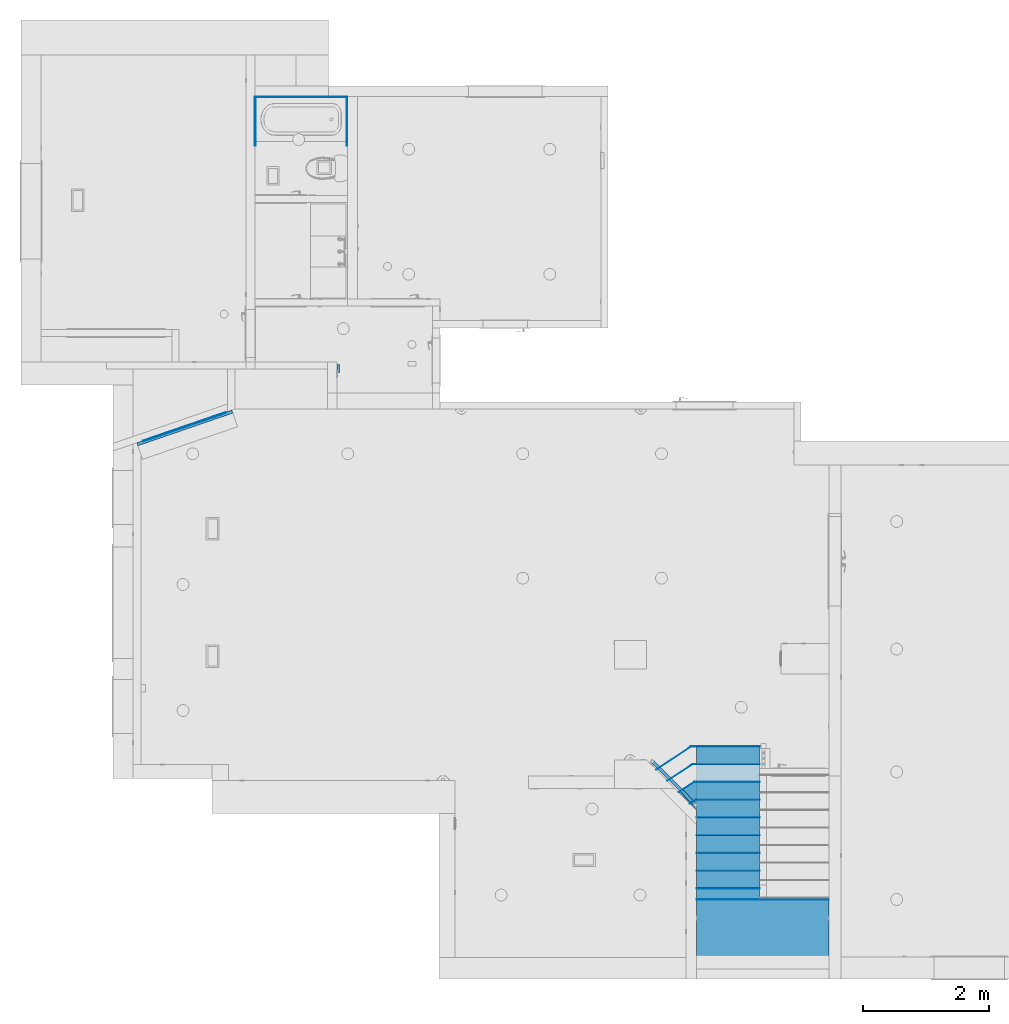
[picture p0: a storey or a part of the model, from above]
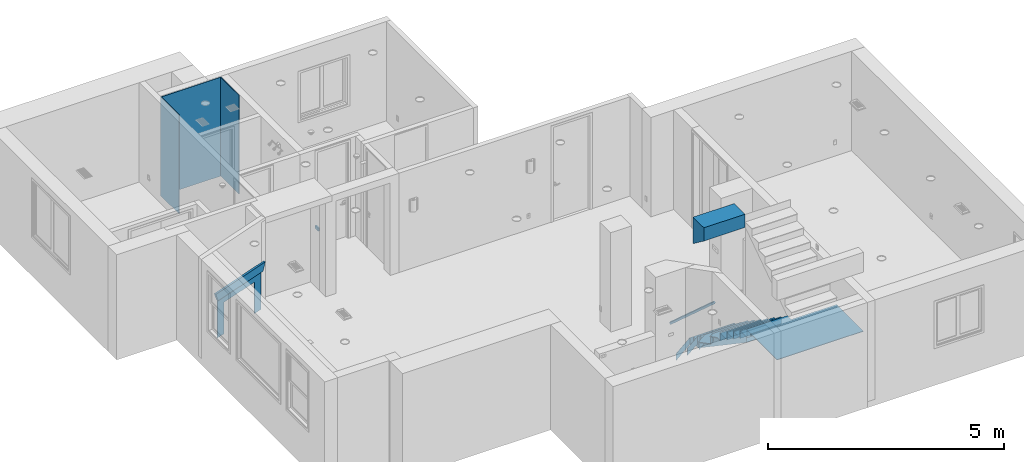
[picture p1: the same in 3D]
Properties of the parts of a building model (IFC2X3)

# File
Description: ViewDefinition [CoordinationView_V2.0, SurfaceGeometryAddOnView], Option [Elements to export: Entire project], Option [Partial Structure Display: Entire Model], Option [IFC Domain: Custom], Option [Structural Function: All Elements], Option [Convert Grid elements: On], Option [Convert IFC Annotations and Archicad 2D elements: Off], Option [Convert 2D symbols of Doors and Windows: On], Option [Export geometries that Participates in Collision Detection only: On], Option [Split complex elements: Off], Option [Material Preservation: Explode where necessary], Option [IFC Model position: Survey Point and Project Origin], Option [Curtain Wall export mode: Single Element], Option [Railing export mode: Single Element], Option [Stair export mode: Single Element], Option [Properties To Export: All properties], Option [Space containment: Off], Option [Geometry to type objects: Off], Option [Element Properties: Off], Option [Building Material Properties: Off], Option [Element Parameters: Off], Option [Component Parameters: Off], Option [IFC Base Quantities: Off], Option [Door Window Parameters: On], Option [IFC Space boundaries: Off], Option [Archicad Zone Categories as IFC Space classification data: Off], Option [Element Classifications: Off]
File name: E:\Twindo\SDP\2 SDP Global USA\SDP Global 28 Google Documents\SDP Global 28.ifc
Time: 2026-05-14T13:14:20
Author: Architect
Organization: Contact Company
Written by: DDS_IFC v3.0
Made in: Graphisoft - Archicad - 28.3.3
Authorization: The authorising person

# IfcSite, Site
RefLatitude: 42, 25, 2, 912200; RefLongitude: -71, -15, -30, -990400; RefElevation: 2568 in

# IfcBuildingStorey (2)
In: Building
Name | Elevation (in)
Second Floor | 128
First Floor | 0

# IfcSpace: Zone Names (25)
InteriorOrExteriorSpace: INTERNAL
Pset_SpaceCommon - Category: Zone Names
AC_Pset_RenovationAndPhasing - Renovation Status: New
Name | In | LongName
019 | First Floor | Hallway
018 | First Floor | Bedroom
020 | First Floor | Living room
013 | First Floor | Bedroom
015 | First Floor | Bathroom
017 | First Floor | Bathroom
014 | First Floor | Storage
021 | First Floor | Living room
03 | Second Floor | Living room
005 | Second Floor | Hallway
03 | Second Floor | Toilet room
002 | Second Floor | Bedroom
009 | Second Floor | Living room
003 | Second Floor | Storage
009 | Second Floor | Toilet room
010 | Second Floor | Hallway
009 | Second Floor | Office
02 | Second Floor | Bathroom
002 | Second Floor | Hallway
011 | Second Floor | Storage
02 | Second Floor | Kitchen
004 | Second Floor | Laundry room
009 | Second Floor | Dining room
007 | Second Floor | Hallway
006 | Second Floor | Storage

# IfcBeam: Generic - Structural 1 1/2" x 3 1/2", BMR - 012
In: Second Floor
Type - PredefinedType: BEAM
Material: Generic - Structural
Pset_BeamCommon - Span: 1.5 in; Slope: 0 rad; FireRating: Undefined; LoadBearing: yes; Reference: Generic - Structural 1 1/2" x 3 1/2"
Pset_PrecastConcreteElementGeneral - ElementWeight: 0 kg
Pset_ConcreteElementGeneral - StructuralClass: Undefined; ConstructionType: Undefined
Pset_FireRatingProperties - FireResistanceRating: Undefined; IsCombustible: no
AC_Pset_RenovationAndPhasing - Renovation Status: Existing

# IfcBeam: Generic - Structural 1 1/2" x 3", BMR - 012
In: First Floor
Type - PredefinedType: BEAM
Material: Generic - Structural
AC_Pset_RenovationAndPhasing - Renovation Status: New
Pset_FireRatingProperties - FireResistanceRating: Undefined; IsCombustible: no
Pset_PrecastConcreteElementGeneral - ElementWeight: 0 kg
Pset_ConcreteElementGeneral - StructuralClass: Undefined; ConstructionType: Undefined
Pset_BeamCommon - Span: 5 in; Slope: 0 rad; FireRating: Undefined; LoadBearing: yes; Reference: Generic - Structural 1 1/2" x 3"

# IfcBeam: Generic - Structural 1 1/2" x 5", BMR - 012
In: Second Floor
Type - PredefinedType: BEAM
Material: Generic - Structural
Pset_BeamCommon - Span: 6.5 in; Slope: 0 rad; FireRating: Undefined; LoadBearing: yes; Reference: Generic - Structural 1 1/2" x 5"
Pset_ConcreteElementGeneral - StructuralClass: Undefined; ConstructionType: Undefined
AC_Pset_RenovationAndPhasing - Renovation Status: New
Pset_FireRatingProperties - FireResistanceRating: Undefined; IsCombustible: no
Pset_PrecastConcreteElementGeneral - ElementWeight: 0 kg

# IfcBeam: Generic - Structural 1" x 5", BMR - 012
In: Second Floor
Type - PredefinedType: BEAM
Material: Generic - Structural
Pset_BeamCommon - Span: 3 in; Slope: 0 rad; FireRating: Undefined; LoadBearing: yes; Reference: Generic - Structural 1" x 5"
Pset_ConcreteElementGeneral - StructuralClass: Undefined; ConstructionType: Undefined
Pset_PrecastConcreteElementGeneral - ElementWeight: 0 kg
Pset_FireRatingProperties - FireResistanceRating: Undefined; IsCombustible: no
AC_Pset_RenovationAndPhasing - Renovation Status: New

# IfcBeam: Generic - Structural 1" x 8 1/2", BMR - 012
In: Second Floor
Type - PredefinedType: BEAM
Material: Generic - Structural
Pset_BeamCommon - Span: 6 in; Slope: 0 rad; FireRating: Undefined; LoadBearing: yes; Reference: Generic - Structural 1" x 8 1/2"
Pset_PrecastConcreteElementGeneral - ElementWeight: 0 kg
Pset_ConcreteElementGeneral - StructuralClass: Undefined; ConstructionType: Undefined
Pset_FireRatingProperties - FireResistanceRating: Undefined; IsCombustible: no
AC_Pset_RenovationAndPhasing - Renovation Status: New

# IfcBeam: Generic - Structural 1/2" x 39", BMR - 113
In: First Floor
Type - PredefinedType: BEAM
Material: Generic - Structural
Pset_ConcreteElementGeneral - StructuralClass: Undefined; ConstructionType: Undefined
Pset_PrecastConcreteElementGeneral - ElementWeight: 0 kg
Pset_BeamCommon - Span: 55 in; Slope: 0 rad; FireRating: Undefined; Reference: Generic - Structural 1/2" x 39"
AC_Pset_RenovationAndPhasing - Renovation Status: Existing
Pset_FireRatingProperties - FireResistanceRating: Undefined; IsCombustible: no

# IfcBeam: Generic - Structural 1/2" x 5" (2)
In: Second Floor
Type - PredefinedType: BEAM
Material: Generic - Structural
Pset_BeamCommon - Span: 7 in; Slope: 0 rad; FireRating: Undefined; LoadBearing: yes; Reference: Generic - Structural 1/2" x 5"
Pset_ConcreteElementGeneral - StructuralClass: Undefined; ConstructionType: Undefined
Pset_PrecastConcreteElementGeneral - ElementWeight: 0 kg
Pset_FireRatingProperties - FireResistanceRating: Undefined; IsCombustible: no
AC_Pset_RenovationAndPhasing - Renovation Status: New
Name
BMR - 012
BMR - 013

# IfcBeam: Generic - Structural 2" x 8" (2)
Type - PredefinedType: BEAM
Material: Generic - Structural
Pset_BeamCommon - Slope: 0 rad; FireRating: Undefined; Reference: Generic - Structural 2" x 8"
Pset_PrecastConcreteElementGeneral - ElementWeight: 0 kg
Pset_FireRatingProperties - FireResistanceRating: Undefined; IsCombustible: no
AC_Pset_RenovationAndPhasing - Renovation Status: Existing
Pset_ConcreteElementGeneral - StructuralClass: Undefined; ConstructionType: Undefined
Name | In | Span (in)
BMR - 113 | First Floor | 57
BMR - 113 | Second Floor | 59

# IfcBeam: Generic - Structural 3/4" x 5", BMR - 012
In: Second Floor
Type - PredefinedType: BEAM
Material: Generic - Structural
Pset_BeamCommon - Span: 4 in; Slope: 0 rad; FireRating: Undefined; LoadBearing: yes; Reference: Generic - Structural 3/4" x 5"
Pset_PrecastConcreteElementGeneral - ElementWeight: 0 kg
Pset_FireRatingProperties - FireResistanceRating: Undefined; IsCombustible: no
AC_Pset_RenovationAndPhasing - Renovation Status: New
Pset_ConcreteElementGeneral - StructuralClass: Undefined; ConstructionType: Undefined

# IfcBeam: Tile - Walls 1/2" x 100 1/2" (3)
In: First Floor
Type - PredefinedType: BEAM
Material: Tile - Walls
Pset_BeamCommon - Slope: 0 rad; FireRating: Undefined; Reference: Tile - Walls 1/2" x 100 1/2"
Pset_ConcreteElementGeneral - StructuralClass: Undefined; ConstructionType: Undefined
Pset_PrecastConcreteElementGeneral - ElementWeight: 0 kg
Pset_FireRatingProperties - FireResistanceRating: Undefined; IsCombustible: no
AC_Pset_RenovationAndPhasing - Renovation Status: Existing
Name | Span (in)
BMR - 005 | 31
BMR - 007 | 31
BMR - 006 | 58.0005

# IfcBeam: Tile - Walls 1/2" x 15" (6)
In: Second Floor
Type - PredefinedType: BEAM
Material: Tile - Walls
Pset_ConcreteElementGeneral - StructuralClass: Undefined; ConstructionType: Undefined
Pset_BeamCommon - Slope: 0 rad; FireRating: Undefined; Reference: Tile - Walls 1/2" x 15"
Pset_PrecastConcreteElementGeneral - ElementWeight: 0 kg
AC_Pset_RenovationAndPhasing - Renovation Status: Existing
Pset_FireRatingProperties - FireResistanceRating: Undefined; IsCombustible: no
Name | Span (in)
BMR - 041 | 24.9997
BMR - 041 | 34.5
BMR - 041 | 40.25
BMR - 041 | 33.5007
BMR - 041 | 49
BMR - 041 | 40

# IfcBeam: Tile - Walls 1/2" x 20" (3)
In: Second Floor
Type - PredefinedType: BEAM
Material: Tile - Walls
Pset_BeamCommon - Slope: 0 rad; FireRating: Undefined; Reference: Tile - Walls 1/2" x 20"
Pset_PrecastConcreteElementGeneral - ElementWeight: 0 kg
Pset_ConcreteElementGeneral - StructuralClass: Undefined; ConstructionType: Undefined
AC_Pset_RenovationAndPhasing - Renovation Status: Existing
Pset_FireRatingProperties - FireResistanceRating: Undefined; IsCombustible: no
Name | Span (in)
BMR - 114 | 72
BMR - 115 | 24
BMR - 113 | 64.25

# IfcBeam: Tile - Walls 1/2" x 44" (6)
In: Second Floor
Type - PredefinedType: BEAM
Material: Tile - Walls
Pset_BeamCommon - Slope: 0 rad; FireRating: Undefined; Reference: Tile - Walls 1/2" x 44"
Pset_ConcreteElementGeneral - StructuralClass: Undefined; ConstructionType: Undefined
Pset_PrecastConcreteElementGeneral - ElementWeight: 0 kg
Pset_FireRatingProperties - FireResistanceRating: Undefined; IsCombustible: no
AC_Pset_RenovationAndPhasing - Renovation Status: Existing
Name | Span (in)
BMR - 113 | 63
BMR - 113 | 2.5
BMR - 113 | 42.636
BMR - 113 | 31.636
BMR - 113 | 39.5
BMR - 113 | 44.3553

# IfcBeam: Tile - Walls 1/2" x 5" (2)
In: Second Floor
Type - PredefinedType: BEAM
Material: Tile - Walls
Pset_BeamCommon - Slope: 0 rad; FireRating: Undefined; Reference: Tile - Walls 1/2" x 5"
Pset_PrecastConcreteElementGeneral - ElementWeight: 0 kg
Pset_FireRatingProperties - FireResistanceRating: Undefined; IsCombustible: no
Pset_ConcreteElementGeneral - StructuralClass: Undefined; ConstructionType: Undefined
AC_Pset_RenovationAndPhasing - Renovation Status: Existing
Name | Span (in)
BMR - 041 | 58
BMR - 041 | 45.9944

# IfcBeam: Tile - Walls 1/2" x 8" (2)
In: Second Floor
Type - PredefinedType: BEAM
Material: Tile - Walls
Pset_BeamCommon - Slope: 0 rad; FireRating: Undefined; Reference: Tile - Walls 1/2" x 8"
Pset_ConcreteElementGeneral - StructuralClass: Undefined; ConstructionType: Undefined
AC_Pset_RenovationAndPhasing - Renovation Status: Existing
Pset_PrecastConcreteElementGeneral - ElementWeight: 0 kg
Pset_FireRatingProperties - FireResistanceRating: Undefined; IsCombustible: no
Name | Span (in)
BMR - 113 | 94
BMR - 112 | 65.5

# IfcBeam: Tile - Walls 1/2" x 97" (4)
In: Second Floor
Type - PredefinedType: BEAM
Material: Tile - Walls
Pset_BeamCommon - Slope: 0 rad; FireRating: Undefined; Reference: Tile - Walls 1/2" x 97"
Pset_PrecastConcreteElementGeneral - ElementWeight: 0 kg
Pset_ConcreteElementGeneral - StructuralClass: Undefined; ConstructionType: Undefined
Pset_FireRatingProperties - FireResistanceRating: Undefined; IsCombustible: no
AC_Pset_RenovationAndPhasing - Renovation Status: Existing
Name | Span (in)
BMR - 004 | 42
BMR - 004 | 64
BMR - 004 | 58
BMR - 004 | 6.05176

# IfcBeam: stairs floor 18" x 27", BMR - 042
In: First Floor
Type - PredefinedType: BEAM
Material: Generic - Structural
Pset_BeamCommon - Span: 39.4966 in; Slope: 0 rad; FireRating: Undefined; Reference: stairs floor 18" x 27"
Pset_ConcreteElementGeneral - StructuralClass: Undefined; ConstructionType: Undefined
Pset_PrecastConcreteElementGeneral - ElementWeight: 0 kg
Pset_FireRatingProperties - FireResistanceRating: Undefined; IsCombustible: no
AC_Pset_RenovationAndPhasing - Renovation Status: Existing

# IfcBuildingElementPart (96)
Material: Wood - Trim
Name | In
8 x Wood - Trim | First Floor
36 x Wood - Trim | First Floor | Pset_FireRatingProperties - FireResistanceRating: Undefined; IsCombustible: no
52 x Wood - Trim | Second Floor

# IfcBuildingElementProxy: Ceiling Ventillator (2)
In: Second Floor
AC_Pset_RenovationAndPhasing - Renovation Status: Existing

# IfcBuildingElementProxy: Color - White (2)
Material: Color - White
AC_Pset_RenovationAndPhasing - Renovation Status: Existing
Name | In
OBJ-03 | First Floor
OBJ-03 | Second Floor

# IfcBuildingElementProxy: D1 (24)
Name | In | Renovation Status
2 x D-09 | First Floor | Existing
D-05 | First Floor | Existing
2 x D-07 | First Floor | Existing
D-11 | First Floor | Existing
D-07 | First Floor | New
D-08 | First Floor | Existing
D-10 | First Floor | Existing
8 x D-07 | Second Floor | Existing
2 x D-09 | Second Floor | Existing
2 x D-08 | Second Floor | Existing
D-09 | Second Floor | New
D-08 | Second Floor | New
D-10 | Second Floor | Existing

# IfcBuildingElementProxy: D2 (2)
AC_Pset_RenovationAndPhasing - Renovation Status: Existing
Name | In
D-06 | First Floor
D-06 | Second Floor

# IfcBuildingElementProxy: D2 Sliding (2)
Name | In | Renovation Status
DOO - 014 | First Floor | Existing
D-15 | Second Floor | New

# IfcBuildingElementProxy: D4 Sliding, D-17
In: Second Floor
AC_Pset_RenovationAndPhasing - Renovation Status: New

# IfcBuildingElementProxy: Fluorescent Lamp (2)
In: Second Floor
AC_Pset_RenovationAndPhasing - Renovation Status: Existing

# IfcBuildingElementProxy: Generic - Structural, MO-02
In: First Floor
Material: Generic - Structural
AC_Pset_RenovationAndPhasing - Renovation Status: Existing

# IfcBuildingElementProxy: Generic - Structural 1 1/2", SLA - 002
In: Second Floor
Material: Generic - Structural
AC_Pset_RenovationAndPhasing - Renovation Status: New

# IfcBuildingElementProxy: Generic - Structural 1/2", SLA - 008
In: Second Floor
Material: Generic - Structural
AC_Pset_RenovationAndPhasing - Renovation Status: Existing

# IfcBuildingElementProxy: Generic - Structural 1/4" (3)
Material: Generic - Structural
Name | In | Renovation Status
SLA - 002 | First Floor | New
S-21 | Second Floor | Existing
SLA - 003 | Second Floor | New

# IfcBuildingElementProxy: Generic - Structural 10 1/2" (2)
Material: Generic - Structural
AC_Pset_RenovationAndPhasing - Renovation Status: Existing
Name | In
SW - 021 | First Floor
SW - 116 | Second Floor

# IfcBuildingElementProxy: Generic - Structural 10" (3)
Material: Generic - Structural
Name | In | Renovation Status
SW - 025 | First Floor | Existing
SW - 016 | First Floor | Existing
SW - 099 | Second Floor | New

# IfcBuildingElementProxy: Generic - Structural 11" (4)
Material: Generic - Structural
AC_Pset_RenovationAndPhasing - Renovation Status: Existing
Name | In
SLA - 003 | First Floor
SLA - 005 | Second Floor
SW - 116 | Second Floor
SW - 089 | Second Floor

# IfcBuildingElementProxy: Generic - Structural 12 1/2" (6)
Material: Generic - Structural
Name | In | Renovation Status
SW - 064 | First Floor | Existing
SW - 019 | First Floor | New
2 x SLA - 015 | Second Floor | Existing
SLA - 013 | Second Floor | Existing
SLA - 011 | Second Floor | Existing

# IfcBuildingElementProxy: Generic - Structural 12 3/4", SW - 048
In: First Floor
Material: Generic - Structural
AC_Pset_RenovationAndPhasing - Renovation Status: Existing

# IfcBuildingElementProxy: Generic - Structural 13 1/2" (3)
In: Second Floor
Material: Generic - Structural
AC_Pset_RenovationAndPhasing - Renovation Status: Existing
Name
2 x SLA - 003
SLA - 009

# IfcBuildingElementProxy: Generic - Structural 13 3/4", SW - 026
In: First Floor
Material: Generic - Structural
AC_Pset_RenovationAndPhasing - Renovation Status: Existing

# IfcBuildingElementProxy: Generic - Structural 14 1/2", SW - 051
In: First Floor
Material: Generic - Structural
AC_Pset_RenovationAndPhasing - Renovation Status: Existing

# IfcBuildingElementProxy: Generic - Structural 14", SW - 063
In: First Floor
Material: Generic - Structural
AC_Pset_RenovationAndPhasing - Renovation Status: Existing

# IfcBuildingElementProxy: Generic - Structural 15", SW - 014
In: First Floor
Material: Generic - Structural
AC_Pset_RenovationAndPhasing - Renovation Status: Existing

# IfcBuildingElementProxy: Generic - Structural 17", SW - 020
In: Second Floor
Material: Generic - Structural
AC_Pset_RenovationAndPhasing - Renovation Status: Existing

# IfcBuildingElementProxy: Generic - Structural 18", SW - 068
In: First Floor
Material: Generic - Structural
AC_Pset_RenovationAndPhasing - Renovation Status: Existing

# IfcBuildingElementProxy: Generic - Structural 18" x 20", C-01
In: First Floor
Material: Generic - Structural
AC_Pset_RenovationAndPhasing - Renovation Status: Existing

# IfcBuildingElementProxy: Generic - Structural 19", SLA - 005
In: Second Floor
Material: Generic - Structural
AC_Pset_RenovationAndPhasing - Renovation Status: Existing

# IfcBuildingElementProxy: Generic - Structural 19" x 30", C-01
In: First Floor
Material: Generic - Structural
AC_Pset_RenovationAndPhasing - Renovation Status: Existing

# IfcBuildingElementProxy: Generic - Structural 2" (4)
Material: Generic - Structural
Name | In | Renovation Status
SLA - 002 | First Floor | New
3 x SW - 076 | Second Floor | Existing

# IfcBuildingElementProxy: Generic - Structural 2" x 9", BMR - 003
In: Second Floor
Material: Generic - Structural
AC_Pset_RenovationAndPhasing - Renovation Status: Existing

# IfcBuildingElementProxy: Generic - Structural 20 1/2" (2)
In: First Floor
Material: Generic - Structural
AC_Pset_RenovationAndPhasing - Renovation Status: Existing
Name
SW - 053
SW - 022

# IfcBuildingElementProxy: Generic - Structural 22", SW - 053
In: First Floor
Material: Generic - Structural
AC_Pset_RenovationAndPhasing - Renovation Status: Existing

# IfcBuildingElementProxy: Generic - Structural 24", S-11
In: Second Floor
Material: Generic - Structural
AC_Pset_RenovationAndPhasing - Renovation Status: Existing

# IfcBuildingElementProxy: Generic - Structural 3 1/2", SW - 014
In: Second Floor
Material: Generic - Structural
AC_Pset_RenovationAndPhasing - Renovation Status: Existing

# IfcBuildingElementProxy: Generic - Structural 34", W-03
In: Second Floor
Material: Generic - Structural
AC_Pset_RenovationAndPhasing - Renovation Status: Existing

# IfcBuildingElementProxy: Generic - Structural 38 3/4", SLA - 006
In: Second Floor
Material: Generic - Structural
AC_Pset_RenovationAndPhasing - Renovation Status: Existing

# IfcBuildingElementProxy: Generic - Structural 38", S-22
In: Second Floor
Material: Generic - Structural
AC_Pset_RenovationAndPhasing - Renovation Status: Existing

# IfcBuildingElementProxy: Generic - Structural 4 1/2" (43)
Material: Generic - Structural
Name | In | Renovation Status
SW - 021 | First Floor | Existing
SW - 054 | First Floor | Existing
2 x SW - 057 | First Floor | Existing
SW - 039 | First Floor | Existing
SW - 066 | First Floor | Existing
SW - 018 | First Floor | Existing
W-16 | First Floor | Existing
SW - 015 | First Floor | Existing
SW - 058 | First Floor | New
SW - 017 | First Floor | Existing
SW - 016 | First Floor | Existing
W-17 | First Floor | Existing
SW - 059 | First Floor | Existing
2 x SW - 051 | First Floor | Existing
SW - 119 | Second Floor | Existing
2 x SW - 106 | Second Floor | Existing
SW - 117 | Second Floor | Existing
SW - 131 | Second Floor | Existing
SW - 115 | Second Floor | Existing
2 x SW - 110 | Second Floor | Existing
2 x SW - 120 | Second Floor | New
SW - 101 | Second Floor | Existing
SW - 137 | Second Floor | Existing
SW - 102 | Second Floor | Existing
SW - 130 | Second Floor | New
SW - 078 | Second Floor | Existing
SW - 100 | Second Floor | Existing
SW - 119 | Second Floor | New
SW - 082 | Second Floor | Existing
SW - 132 | Second Floor | Existing
SW - 138 | Second Floor | Existing
SW - 015 | Second Floor | Existing
SW - 084 | Second Floor | Existing
SW - 075 | Second Floor | Existing
SW - 135 | Second Floor | Existing
SW - 107 | Second Floor | Existing
2 x W-03 | Second Floor | Existing

# IfcBuildingElementProxy: Generic - Structural 4 3/4", SLA - 005
In: Second Floor
Material: Generic - Structural
AC_Pset_RenovationAndPhasing - Renovation Status: Existing

# IfcBuildingElementProxy: Generic - Structural 4", SW - 020
In: Second Floor
Material: Generic - Structural
AC_Pset_RenovationAndPhasing - Renovation Status: Existing

# IfcBuildingElementProxy: Generic - Structural 5 1/2" (7)
Material: Generic - Structural
Name | In | Renovation Status
SW - 052 | First Floor | Existing
SW - 077 | Second Floor | Existing
SW - 106 | Second Floor | New
SW - 126 | Second Floor | Existing
SW - 095 | Second Floor | Existing
SW - 104 | Second Floor | Existing
SW - 079 | Second Floor | Existing

# IfcBuildingElementProxy: Generic - Structural 5", S-11
In: Second Floor
Material: Generic - Structural
AC_Pset_RenovationAndPhasing - Renovation Status: Existing

# IfcBuildingElementProxy: Generic - Structural 52", S-10
In: Second Floor
Material: Generic - Structural
AC_Pset_RenovationAndPhasing - Renovation Status: Existing

# IfcBuildingElementProxy: Generic - Structural 6 1/2" (32)
Material: Generic - Structural
Name | In | Renovation Status
SW - 037 | First Floor | Existing
SW - 036 | First Floor | Existing
SW - 055 | First Floor | Existing
SW - 146 | First Floor | Existing
SW - 056 | First Floor | Existing
SW - 035 | First Floor | Existing
SW - 087 | Second Floor | Existing
SW - 118 | Second Floor | Existing
2 x SW - 120 | Second Floor | Existing
2 x SW - 102 | Second Floor | Existing
SW - 076 | Second Floor | Existing
SW - 134 | Second Floor | Existing
SW - 129 | Second Floor | Existing
SLA - 004 | Second Floor | Existing
SW - 116 | Second Floor | Existing
SW - 099 | Second Floor | New
SW - 122 | Second Floor | Existing
SW - 121 | Second Floor | Existing
2 x SW - 093 | Second Floor | New
SW - 080 | Second Floor | Existing
SW - 109 | Second Floor | Existing
SW - 136 | Second Floor | Existing
SW - 123 | Second Floor | Existing
SW - 145 | Second Floor | Existing
SW - 086 | Second Floor | Existing
2 x SW - 088 | Second Floor | Existing
SW - 112 | Second Floor | New
SW - 105 | Second Floor | Existing

# IfcBuildingElementProxy: Generic - Structural 6 3/4", SW - 080
In: Second Floor
Material: Generic - Structural
AC_Pset_RenovationAndPhasing - Renovation Status: Existing

# IfcBuildingElementProxy: Generic - Structural 6" (10)
Material: Generic - Structural
AC_Pset_RenovationAndPhasing - Renovation Status: Existing
Name | In
SW - 067 | First Floor
SLA - 002 | First Floor
SLA - 003 | First Floor
2 x SLA - 016 | Second Floor
SLA - 017 | Second Floor
SLA - 007 | Second Floor
SLA - 006 | Second Floor
SLA - 018 | Second Floor
SLA - 002 | Second Floor

# IfcBuildingElementProxy: Generic - Structural 7 1/2" (6)
Material: Generic - Structural
AC_Pset_RenovationAndPhasing - Renovation Status: Existing
Name | In
3 x SW - 044 | First Floor
SLA - 010 | Second Floor
SW - 130 | Second Floor
SW - 102 | Second Floor

# IfcBuildingElementProxy: Generic - Structural 7", SW - 116
In: Second Floor
Material: Generic - Structural
AC_Pset_RenovationAndPhasing - Renovation Status: Existing

# IfcBuildingElementProxy: Generic - Structural 8 1/2" (6)
Material: Generic - Structural
Name | In | Renovation Status
SW - 024 | First Floor | Existing
SW - 020 | First Floor | New
SW - 129 | Second Floor | Existing
SW - 111 | Second Floor | Existing
SW - 090 | Second Floor | Existing
SW - 092 | Second Floor | Existing

# IfcBuildingElementProxy: Generic - Structural 8" (9)
Material: Generic - Structural
AC_Pset_RenovationAndPhasing - Renovation Status: Existing
Name | In
SW - 073 | First Floor
2 x SW - 128 | Second Floor
SW - 018 | Second Floor
2 x SW - 124 | Second Floor
SW - 116 | Second Floor
SLA - 012 | Second Floor
SW - 081 | Second Floor

# IfcBuildingElementProxy: Generic - Structural 9 1/2", SW - 108
In: Second Floor
Material: Generic - Structural
AC_Pset_RenovationAndPhasing - Renovation Status: Existing

# IfcBuildingElementProxy: Generic - Structural 9", SW - 086
In: Second Floor
Material: Generic - Structural
AC_Pset_RenovationAndPhasing - Renovation Status: Existing

# IfcBuildingElementProxy: Generic Floor/Ceiling Slab 6" 6", SLA - 008
In: Second Floor
Material: Generic - Structural
AC_Pset_RenovationAndPhasing - Renovation Status: Existing

# IfcBuildingElementProxy: Pendant Lamp (8)
In: Second Floor
AC_Pset_RenovationAndPhasing - Renovation Status: Existing

# IfcBuildingElementProxy: Railing Type (8)
Name | In | Renovation Status
RAILING - 001 | First Floor | Existing
RA-07 | First Floor | New
2 x RAILING - 001 | Second Floor | Existing
3 x RA-07 | Second Floor | New
RA-03 | Second Floor | Existing

# IfcBuildingElementProxy: Recessed Spot (52)
Name | In | Renovation Status
26 x L-03 | First Floor | New
20 x L-03 | Second Floor | Existing
6 x L-03 | Second Floor | New

# IfcBuildingElementProxy: Shower Door, OBJ-23
In: Second Floor
AC_Pset_RenovationAndPhasing - Renovation Status: Existing

# IfcBuildingElementProxy: Smoke and Heat Detector (5)
Name | In | Renovation Status
3 x OBJ-13 | First Floor | New
2 x OBJ-13 | Second Floor | Existing

# IfcBuildingElementProxy: W Double Hung (7)
Name | In | Renovation Status
2 x WD - 001 | First Floor | New
5 x WD - 002 | Second Floor | Existing

# IfcBuildingElementProxy: W Double Sash (4)
Name | In | Renovation Status
2 x WD - 001 | First Floor | Existing
W-02 | First Floor | Existing
WD - 001 | Second Floor | New

# IfcBuildingElementProxy: W Fixed (15)
In: Second Floor
Name | Renovation Status
10 x WD - 002 | Existing
5 x WD - 002 | New

# IfcBuildingElementProxy: W1 Casement (4)
Name | In | Renovation Status
WD - 001 | First Floor | New
3 x WD - 001 | Second Floor | Existing

# IfcBuildingElementProxy: Wall Lamp (6)
AC_Pset_RenovationAndPhasing - Renovation Status: Existing
Name | In
4 x L-17 | First Floor
2 x L-17 | Second Floor

# IfcBuildingElementProxy: Wall Spotlight (4)
Name | In | Renovation Status
L-23 | First Floor | Existing
3 x L-23 | Second Floor | New

# IfcDistributionFlowElement: Basin, OBJ-24
In: Second Floor
Pset_ManufacturerOccurrence - BarCode: Undefined; AcquisitionDate: MM/DD/YYYY
AC_Pset_RenovationAndPhasing - Renovation Status: Existing
Pset_ManufacturerTypeInformation - ModelLabel: Undefined
Pset_Warranty - WarrantyEndDate: MM/DD/YYYY

# IfcDistributionFlowElement: Bathtub, OBJ-19
In: First Floor
Pset_ManufacturerOccurrence - BarCode: Undefined; AcquisitionDate: MM/DD/YYYY
Pset_ManufacturerTypeInformation - ModelLabel: Undefined
AC_Pset_RenovationAndPhasing - Renovation Status: Existing
Pset_Warranty - WarrantyEndDate: MM/DD/YYYY

# IfcDistributionFlowElement: Ceiling Grille (12)
Pset_ManufacturerTypeInformation - ModelLabel: Undefined
Pset_ManufacturerOccurrence - BarCode: Undefined; AcquisitionDate: MM/DD/YYYY
AC_Pset_RenovationAndPhasing - Renovation Status: Existing
Pset_Warranty - WarrantyEndDate: MM/DD/YYYY
Name | In
5 x FU - 013 | First Floor
3 x FU - 007 | First Floor
4 x FU - 007 | Second Floor

# IfcDistributionFlowElement: Dishwasher Built-in, OBJ-18
In: Second Floor
Pset_ManufacturerOccurrence - BarCode: Undefined; AcquisitionDate: MM/DD/YYYY
Pset_Warranty - WarrantyEndDate: MM/DD/YYYY
AC_Pset_RenovationAndPhasing - Renovation Status: Existing
Pset_ManufacturerTypeInformation - ModelLabel: Undefined

# IfcDistributionFlowElement: Freestanding Bathtub, OBJ-21
In: Second Floor
Pset_ManufacturerTypeInformation - ModelLabel: Undefined
Pset_ManufacturerOccurrence - BarCode: Undefined; AcquisitionDate: MM/DD/YYYY
Pset_Warranty - WarrantyEndDate: MM/DD/YYYY
AC_Pset_RenovationAndPhasing - Renovation Status: Existing

# IfcDistributionFlowElement: Hood, OBJ-21
In: Second Floor
Pset_ManufacturerTypeInformation - ModelLabel: Undefined
Pset_ManufacturerOccurrence - BarCode: Undefined; AcquisitionDate: MM/DD/YYYY
Pset_Warranty - WarrantyEndDate: MM/DD/YYYY
AC_Pset_RenovationAndPhasing - Renovation Status: Existing

# IfcDistributionFlowElement: Rect Floor Register (7)
In: Second Floor
Pset_ManufacturerOccurrence - BarCode: Undefined; AcquisitionDate: MM/DD/YYYY
Pset_Warranty - WarrantyEndDate: MM/DD/YYYY
Pset_ManufacturerTypeInformation - ModelLabel: Undefined
AC_Pset_RenovationAndPhasing - Renovation Status: Existing

# IfcDistributionFlowElement: Sidewall Grille (6)
Pset_ManufacturerOccurrence - BarCode: Undefined; AcquisitionDate: MM/DD/YYYY
Pset_ManufacturerTypeInformation - ModelLabel: Undefined
Pset_Warranty - WarrantyEndDate: MM/DD/YYYY
AC_Pset_RenovationAndPhasing - Renovation Status: Existing
Name | In
FU - 004 | First Floor
5 x FU - 004 | Second Floor

# IfcDistributionFlowElement: WC (3)
Pset_ManufacturerTypeInformation - ModelLabel: Undefined
Pset_ManufacturerOccurrence - BarCode: Undefined; AcquisitionDate: MM/DD/YYYY
Pset_Warranty - WarrantyEndDate: MM/DD/YYYY
Name | In | Renovation Status
OBJ-18 | First Floor | Existing
2 x OBJ-18 | Second Floor | New

# IfcDistributionFlowElement: Washer (2)
In: Second Floor
Pset_ManufacturerOccurrence - BarCode: Undefined; AcquisitionDate: MM/DD/YYYY
AC_Pset_RenovationAndPhasing - Renovation Status: Existing
Pset_ManufacturerTypeInformation - ModelLabel: Undefined
Pset_Warranty - WarrantyEndDate: MM/DD/YYYY

# IfcFlowController: Outlet 1 US (95)
Pset_ManufacturerTypeInformation - ModelLabel: Undefined
Pset_Warranty - WarrantyEndDate: MM/DD/YYYY
Pset_ManufacturerOccurrence - BarCode: Undefined; AcquisitionDate: MM/DD/YYYY
Name | In | Renovation Status
35 x FU - 029 | First Floor | Existing
15 x OBJ-05 | First Floor | New
28 x FU - 029 | Second Floor | Existing
17 x OBJ-05 | Second Floor | Existing

# IfcFlowController: Switch US (35)
Pset_ManufacturerOccurrence - BarCode: Undefined; AcquisitionDate: MM/DD/YYYY
AC_Pset_RenovationAndPhasing - Renovation Status: Existing
Pset_Warranty - WarrantyEndDate: MM/DD/YYYY
Pset_ManufacturerTypeInformation - ModelLabel: Undefined
Name | In
8 x OBJ-09 | First Floor
27 x OBJ-09 | Second Floor

# IfcFlowTerminal: Gas Stove, OBJ-24
In: Second Floor
Pset_ManufacturerOccurrence - BarCode: Undefined; AcquisitionDate: MM/DD/YYYY
Pset_ManufacturerTypeInformation - ModelLabel: Undefined
AC_Pset_RenovationAndPhasing - Renovation Status: Existing
Pset_Warranty - WarrantyEndDate: MM/DD/YYYY

# IfcFlowTerminal: Oven Built-in (2)
In: Second Floor
Pset_Warranty - WarrantyEndDate: MM/DD/YYYY
AC_Pset_RenovationAndPhasing - Renovation Status: Existing
Pset_ManufacturerOccurrence - BarCode: Undefined; AcquisitionDate: MM/DD/YYYY
Pset_ManufacturerTypeInformation - ModelLabel: Undefined
Name
OBJ-20
OBJ-19

# IfcFlowTerminal: Refrigerator, OBJ-20
In: Second Floor
Pset_ManufacturerOccurrence - BarCode: Undefined; AcquisitionDate: MM/DD/YYYY
Pset_ManufacturerTypeInformation - ModelLabel: Undefined
AC_Pset_RenovationAndPhasing - Renovation Status: Existing
Pset_Warranty - WarrantyEndDate: MM/DD/YYYY

# IfcFurnishingElement: Base Cabinet Block (26)
Pset_ManufacturerTypeInformation - ModelLabel: Undefined
Pset_ManufacturerOccurrence - BarCode: Undefined; AcquisitionDate: MM/DD/YYYY
AC_Pset_RenovationAndPhasing - Renovation Status: Existing
Pset_Warranty - WarrantyEndDate: MM/DD/YYYY
Name | In
3 x FU - 030 | First Floor
4 x FU - 004 | Second Floor
2 x FU - 025 | Second Floor
3 x FU - 007 | Second Floor
12 x OBJ-16 | Second Floor
OBJ-15 | Second Floor
FU - 026 | Second Floor

# IfcFurnishingElement: Base Cabinet Corner L, FU - 025
In: Second Floor
Pset_ManufacturerTypeInformation - ModelLabel: Undefined
Pset_ManufacturerOccurrence - BarCode: Undefined; AcquisitionDate: MM/DD/YYYY
Pset_Warranty - WarrantyEndDate: MM/DD/YYYY
AC_Pset_RenovationAndPhasing - Renovation Status: Existing

# IfcFurnishingElement: Standing Cabinet Block (2)
In: Second Floor
Pset_ManufacturerOccurrence - BarCode: Undefined; AcquisitionDate: MM/DD/YYYY
Pset_ManufacturerTypeInformation - ModelLabel: Undefined
Pset_Warranty - WarrantyEndDate: MM/DD/YYYY
AC_Pset_RenovationAndPhasing - Renovation Status: Existing

# IfcFurnishingElement: Wall Cabinet Block (16)
In: Second Floor
Pset_ManufacturerOccurrence - BarCode: Undefined; AcquisitionDate: MM/DD/YYYY
Pset_ManufacturerTypeInformation - ModelLabel: Undefined
Pset_Warranty - WarrantyEndDate: MM/DD/YYYY
AC_Pset_RenovationAndPhasing - Renovation Status: Existing
Name
7 x OBJ-21
6 x FU - 005
3 x FU - 008

# IfcSlab: Generic - Structural 27", S-03
In: Second Floor
Type - PredefinedType: FLOOR
Material: Generic - Structural
Pset_ConcreteElementGeneral - StructuralClass: Undefined; ConstructionType: Undefined
Pset_PrecastConcreteElementGeneral - ElementWeight: 0 kg
Pset_SlabCommon - AcousticRating: Undefined; FireRating: Undefined; Combustible: no; ThermalTransmittance: 0; IsExternal: no; LoadBearing: yes
AC_Pset_RenovationAndPhasing - Renovation Status: Existing
Pset_FireRatingProperties - FireResistanceRating: Undefined; IsCombustible: no

# IfcStair (3)
In: First Floor
Pset_ConcreteElementGeneral - StructuralClass: Undefined; ConstructionType: Undefined
Pset_StairCommon - RequiredHeadroom: 80 in; FireRating: Undefined; HasNonSkidSurface: no; IsExternal: no
AC_Pset_RenovationAndPhasing - Renovation Status: New
Pset_FireRatingProperties - FireResistanceRating: Undefined; IsCombustible: no
Name | NumberOfRiser | NumberOfTreads | RiserHeight (in)
STAIR-01 | 8 | 7 | 7.5
STAIR-01 | 1 | 1 | 2
STAIR-01 | 9 | 8 | 7.52778
